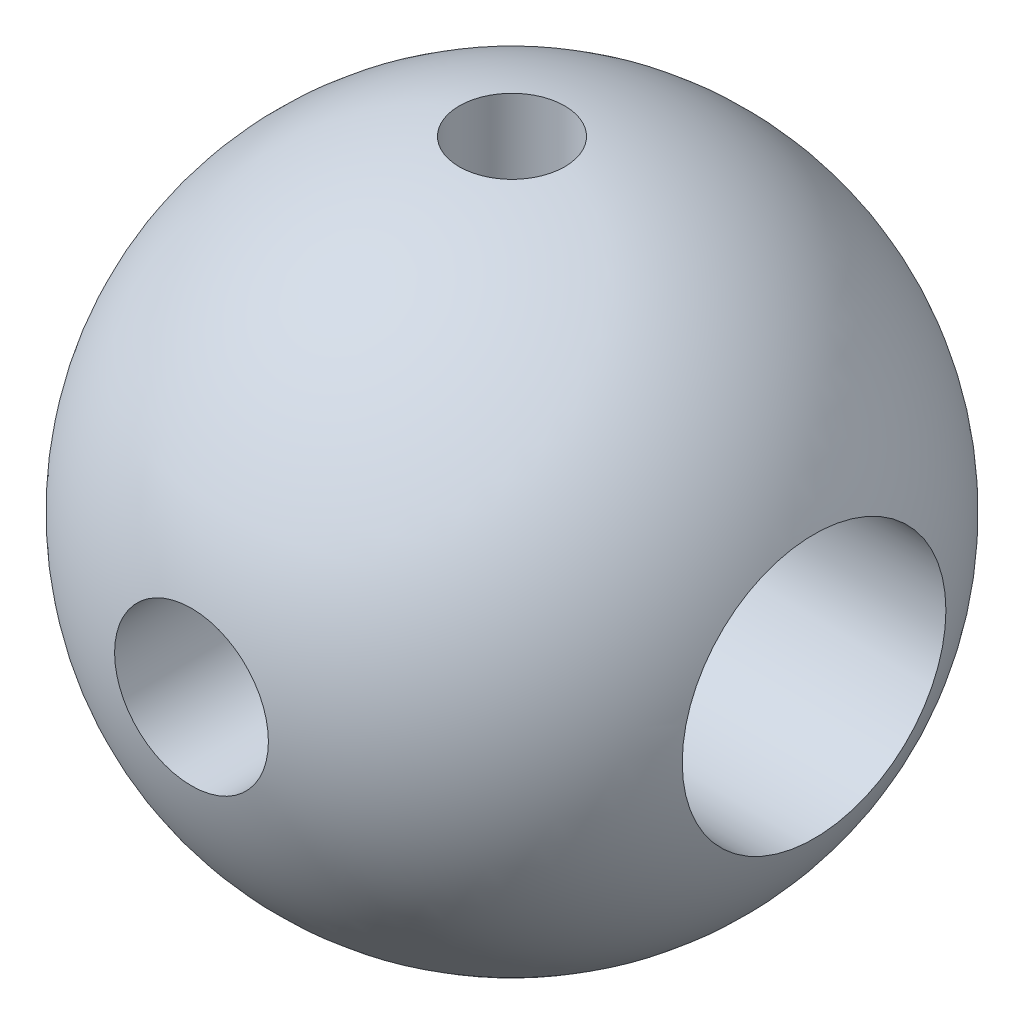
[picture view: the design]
ISO-10303-21;
HEADER;
FILE_DESCRIPTION(('STEP AP214'),'2;1');
FILE_NAME('part.step','',(''),(''),'','','');
FILE_SCHEMA(('AUTOMOTIVE_DESIGN { 1 0 10303 214 1 1 1 1 }'));
ENDSEC;
DATA;
#1=APPLICATION_CONTEXT('core data for automotive mechanical design processes');
#2=APPLICATION_PROTOCOL_DEFINITION('international standard','automotive_design',2000,#1);
#3=PRODUCT_CONTEXT('',#1,'mechanical');
#4=PRODUCT('Part','Part','',(#3));
#5=PRODUCT_RELATED_PRODUCT_CATEGORY('part','',(#4));
#6=PRODUCT_DEFINITION_FORMATION('','',#4);
#7=PRODUCT_DEFINITION_CONTEXT('part definition',#1,'design');
#8=PRODUCT_DEFINITION('design','',#6,#7);
#9=PRODUCT_DEFINITION_SHAPE('','',#8);
#10=(LENGTH_UNIT() NAMED_UNIT(*) SI_UNIT(.MILLI.,.METRE.));
#11=(NAMED_UNIT(*) PLANE_ANGLE_UNIT() SI_UNIT($,.RADIAN.));
#12=(NAMED_UNIT(*) SI_UNIT($,.STERADIAN.) SOLID_ANGLE_UNIT());
#13=UNCERTAINTY_MEASURE_WITH_UNIT(LENGTH_MEASURE(1.E-05),#10,'distance_accuracy_value','');
#14=(GEOMETRIC_REPRESENTATION_CONTEXT(3) GLOBAL_UNCERTAINTY_ASSIGNED_CONTEXT((#13)) GLOBAL_UNIT_ASSIGNED_CONTEXT((#10,
#11,#12)) REPRESENTATION_CONTEXT('',''));
#15=CARTESIAN_POINT('',(0.,0.,0.));
#16=DIRECTION('',(0.,0.,1.));
#17=DIRECTION('',(1.,0.,0.));
#18=AXIS2_PLACEMENT_3D('',#15,#16,#17);
#19=CARTESIAN_POINT('',(0.,0.,-75.));
#20=DIRECTION('',(0.,0.,1.));
#21=DIRECTION('',(1.,0.,0.));
#22=AXIS2_PLACEMENT_3D('',#19,#20,#21);
#23=CYLINDRICAL_SURFACE('',#22,17.5);
#24=CARTESIAN_POINT('',(17.5,0.,-30.));
#25=CARTESIAN_POINT('',(17.4999968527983,0.449810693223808,-29.9999971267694));
#26=CARTESIAN_POINT('',(17.4826284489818,0.899793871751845,-29.9898563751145));
#27=CARTESIAN_POINT('',(17.4133677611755,1.79639765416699,-29.9495342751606));
#28=CARTESIAN_POINT('',(17.361451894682,2.24301575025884,-29.919339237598));
#29=CARTESIAN_POINT('',(17.2236137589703,3.13036631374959,-29.8395660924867));
#30=CARTESIAN_POINT('',(17.1376074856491,3.57108144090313,-29.789940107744));
#31=CARTESIAN_POINT('',(16.9327162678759,4.44222245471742,-29.6725435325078));
#32=CARTESIAN_POINT('',(16.8138366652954,4.8726500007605,-29.6047758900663));
#33=CARTESIAN_POINT('',(16.5452616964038,5.71841043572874,-29.453072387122));
#34=CARTESIAN_POINT('',(16.3957215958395,6.13380743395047,-29.3692181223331));
#35=CARTESIAN_POINT('',(16.0670205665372,6.94940208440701,-29.1869910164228));
#36=CARTESIAN_POINT('',(15.8878585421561,7.34959917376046,-29.0886176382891));
#37=CARTESIAN_POINT('',(15.5016401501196,8.13262843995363,-28.8794824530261));
#38=CARTESIAN_POINT('',(15.2945981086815,8.5154694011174,-28.7687270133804));
#39=CARTESIAN_POINT('',(14.8541334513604,9.26243782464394,-28.5369970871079));
#40=CARTESIAN_POINT('',(14.6207082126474,9.62656342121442,-28.4160215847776));
#41=CARTESIAN_POINT('',(14.1107946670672,10.3609767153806,-28.1569314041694));
#42=CARTESIAN_POINT('',(13.8323977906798,10.7297256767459,-28.0182109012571));
#43=CARTESIAN_POINT('',(13.2486479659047,11.4427112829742,-27.7346638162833));
#44=CARTESIAN_POINT('',(12.9432938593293,11.7869468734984,-27.5898369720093));
#45=CARTESIAN_POINT('',(12.3067916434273,12.4500740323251,-27.2970177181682));
#46=CARTESIAN_POINT('',(11.9756138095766,12.7689355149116,-27.1490218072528));
#47=CARTESIAN_POINT('',(11.2891441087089,13.3796980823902,-26.853283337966));
#48=CARTESIAN_POINT('',(10.9338509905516,13.6715977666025,-26.7055407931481));
#49=CARTESIAN_POINT('',(10.1583817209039,14.259039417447,-26.3970089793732));
#50=CARTESIAN_POINT('',(9.73543487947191,14.5511698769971,-26.2366633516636));
#51=CARTESIAN_POINT('',(8.86283360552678,15.0985250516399,-25.9255412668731));
#52=CARTESIAN_POINT('',(8.41317514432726,15.3537441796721,-25.774766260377));
#53=CARTESIAN_POINT('',(7.48977052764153,15.8247150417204,-25.4883167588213));
#54=CARTESIAN_POINT('',(7.01605587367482,16.0405167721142,-25.3526232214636));
#55=CARTESIAN_POINT('',(6.04663430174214,16.4304876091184,-25.1016518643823));
#56=CARTESIAN_POINT('',(5.55093507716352,16.6046711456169,-24.9863669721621));
#57=CARTESIAN_POINT('',(4.65706076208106,16.8738511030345,-24.8051015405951));
#58=CARTESIAN_POINT('',(4.26263870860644,16.9778465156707,-24.7338784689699));
#59=CARTESIAN_POINT('',(3.46485026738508,17.1584379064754,-24.6089435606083));
#60=CARTESIAN_POINT('',(3.06148523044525,17.2350379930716,-24.5552290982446));
#61=CARTESIAN_POINT('',(2.24867486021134,17.3597911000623,-24.4671923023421));
#62=CARTESIAN_POINT('',(1.8392358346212,17.4079717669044,-24.4328511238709));
#63=CARTESIAN_POINT('',(1.0167506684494,17.475309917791,-24.3847344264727));
#64=CARTESIAN_POINT('',(0.603704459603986,17.4944668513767,-24.3709592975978));
#65=CARTESIAN_POINT('',(-0.223533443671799,17.5034683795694,-24.3644952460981));
#66=CARTESIAN_POINT('',(-0.637725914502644,17.4932661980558,-24.37183997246));
#67=CARTESIAN_POINT('',(-1.46344007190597,17.4436068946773,-24.4074066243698));
#68=CARTESIAN_POINT('',(-1.87496174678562,17.4041496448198,-24.4356286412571));
#69=CARTESIAN_POINT('',(-2.692603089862,17.2965326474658,-24.5119213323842));
#70=CARTESIAN_POINT('',(-3.09871931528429,17.2283554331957,-24.5600040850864));
#71=CARTESIAN_POINT('',(-3.90267086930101,17.0642171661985,-24.674328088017));
#72=CARTESIAN_POINT('',(-4.30050600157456,16.9682554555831,-24.7405697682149));
#73=CARTESIAN_POINT('',(-5.08267223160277,16.7505223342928,-24.8884945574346));
#74=CARTESIAN_POINT('',(-5.46708355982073,16.6289547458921,-24.970055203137));
#75=CARTESIAN_POINT('',(-6.22398496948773,16.3607241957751,-25.1466195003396));
#76=CARTESIAN_POINT('',(-6.59647109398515,16.2140530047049,-25.2416275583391));
#77=CARTESIAN_POINT('',(-7.32806526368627,15.8968063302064,-25.4426176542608));
#78=CARTESIAN_POINT('',(-7.6871723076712,15.7262290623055,-25.5486005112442));
#79=CARTESIAN_POINT('',(-8.39091146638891,15.3622772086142,-25.7690843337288));
#80=CARTESIAN_POINT('',(-8.73554280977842,15.1689014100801,-25.8835857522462));
#81=CARTESIAN_POINT('',(-9.46560202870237,14.7262927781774,-26.1383221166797));
#82=CARTESIAN_POINT('',(-9.84826032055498,14.4731215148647,-26.2796660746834));
#83=CARTESIAN_POINT('',(-10.5913084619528,13.938566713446,-26.5670554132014));
#84=CARTESIAN_POINT('',(-10.9517021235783,13.6571880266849,-26.7130999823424));
#85=CARTESIAN_POINT('',(-11.6494208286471,13.0671312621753,-27.0066427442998));
#86=CARTESIAN_POINT('',(-11.9867237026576,12.7584275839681,-27.1541421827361));
#87=CARTESIAN_POINT('',(-12.6365789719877,12.1151118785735,-27.4472042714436));
#88=CARTESIAN_POINT('',(-12.9491301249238,11.7804985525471,-27.5927668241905));
#89=CARTESIAN_POINT('',(-13.5852520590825,11.0433879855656,-27.8966228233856));
#90=CARTESIAN_POINT('',(-13.905367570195,10.6376217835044,-28.0542511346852));
#91=CARTESIAN_POINT('',(-14.5101413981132,9.79663499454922,-28.358878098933));
#92=CARTESIAN_POINT('',(-14.7947962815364,9.36141156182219,-28.5058757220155));
#93=CARTESIAN_POINT('',(-15.3258939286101,8.46396420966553,-28.7851006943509));
#94=CARTESIAN_POINT('',(-15.5723530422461,8.00175196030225,-28.9173343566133));
#95=CARTESIAN_POINT('',(-16.024383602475,7.0530224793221,-29.1632455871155));
#96=CARTESIAN_POINT('',(-16.2299601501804,6.56650828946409,-29.2769254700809));
#97=CARTESIAN_POINT('',(-16.585129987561,5.60604764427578,-29.4753513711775));
#98=CARTESIAN_POINT('',(-16.7375511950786,5.13344287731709,-29.5615255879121));
#99=CARTESIAN_POINT('',(-17.0022860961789,4.17372530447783,-29.7122175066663));
#100=CARTESIAN_POINT('',(-17.114601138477,3.68661298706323,-29.776735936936));
#101=CARTESIAN_POINT('',(-17.2973035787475,2.70250384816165,-29.8821207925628));
#102=CARTESIAN_POINT('',(-17.3677283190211,2.20551623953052,-29.9230082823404));
#103=CARTESIAN_POINT('',(-17.4656178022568,1.2059347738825,-29.9799298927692));
#104=CARTESIAN_POINT('',(-17.4930878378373,0.703341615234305,-29.9959670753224));
#105=CARTESIAN_POINT('',(-17.5038812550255,-0.238332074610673,-30.0022648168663));
#106=CARTESIAN_POINT('',(-17.4923847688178,-0.677343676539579,-29.9955500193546));
#107=CARTESIAN_POINT('',(-17.4365101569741,-1.55252162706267,-29.962999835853));
#108=CARTESIAN_POINT('',(-17.39213540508,-1.98868826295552,-29.9371664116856));
#109=CARTESIAN_POINT('',(-17.2710852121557,-2.85498146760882,-29.8670045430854));
#110=CARTESIAN_POINT('',(-17.1944102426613,-3.28510812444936,-29.8226763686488));
#111=CARTESIAN_POINT('',(-17.009706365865,-4.13637468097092,-29.7165677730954));
#112=CARTESIAN_POINT('',(-16.9016765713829,-4.55751432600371,-29.654786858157));
#113=CARTESIAN_POINT('',(-16.6574538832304,-5.38154043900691,-29.5162806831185));
#114=CARTESIAN_POINT('',(-16.5217352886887,-5.78461054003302,-29.439808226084));
#115=CARTESIAN_POINT('',(-16.2224830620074,-6.57727299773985,-29.2729147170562));
#116=CARTESIAN_POINT('',(-16.058950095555,-6.96686567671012,-29.1824939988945));
#117=CARTESIAN_POINT('',(-15.7054857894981,-7.73077402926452,-28.989487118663));
#118=CARTESIAN_POINT('',(-15.5155522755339,-8.10508844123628,-28.8868999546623));
#119=CARTESIAN_POINT('',(-15.1107192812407,-8.83691529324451,-28.6714922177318));
#120=CARTESIAN_POINT('',(-14.8958168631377,-9.19442574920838,-28.5586704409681));
#121=CARTESIAN_POINT('',(-14.4187917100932,-9.9276976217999,-28.3126392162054));
#122=CARTESIAN_POINT('',(-14.1540817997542,-10.3014755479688,-28.178530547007));
#123=CARTESIAN_POINT('',(-13.5976432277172,-11.0255438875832,-27.9031798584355));
#124=CARTESIAN_POINT('',(-13.3059129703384,-11.3758329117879,-27.7619374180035));
#125=CARTESIAN_POINT('',(-12.6966614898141,-12.0520590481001,-27.4751323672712));
#126=CARTESIAN_POINT('',(-12.3791126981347,-12.3779693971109,-27.3295652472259));
#127=CARTESIAN_POINT('',(-11.719891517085,-13.0038744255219,-27.0373548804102));
#128=CARTESIAN_POINT('',(-11.3782184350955,-13.3038683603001,-26.8907116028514));
#129=CARTESIAN_POINT('',(-10.629716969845,-13.9110859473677,-26.5821575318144));
#130=CARTESIAN_POINT('',(-10.219984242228,-14.2148796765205,-26.4205194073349));
#131=CARTESIAN_POINT('',(-9.37347588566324,-14.7867809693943,-26.1047476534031));
#132=CARTESIAN_POINT('',(-8.93669617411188,-15.0548831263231,-25.9506151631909));
#133=CARTESIAN_POINT('',(-8.03840403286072,-15.5530565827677,-25.6551405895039));
#134=CARTESIAN_POINT('',(-7.57691649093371,-15.7831652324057,-25.5137860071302));
#135=CARTESIAN_POINT('',(-6.63112032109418,-16.2032645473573,-25.2490774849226));
#136=CARTESIAN_POINT('',(-6.14681879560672,-16.3932675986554,-25.1257179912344));
#137=CARTESIAN_POINT('',(-5.26494928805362,-16.6942555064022,-24.9264319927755));
#138=CARTESIAN_POINT('',(-4.87118142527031,-16.8134449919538,-24.8460125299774));
#139=CARTESIAN_POINT('',(-4.07333959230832,-17.0243377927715,-24.7019890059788));
#140=CARTESIAN_POINT('',(-3.66926705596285,-17.1160449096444,-24.6383826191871));
#141=CARTESIAN_POINT('',(-2.85358320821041,-17.270761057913,-24.5301802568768));
#142=CARTESIAN_POINT('',(-2.44198036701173,-17.3338004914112,-24.4855641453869));
#143=CARTESIAN_POINT('',(-1.61360456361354,-17.430437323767,-24.4168669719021));
#144=CARTESIAN_POINT('',(-1.19683154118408,-17.4640343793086,-24.3927861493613));
#145=CARTESIAN_POINT('',(-0.360120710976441,-17.5013184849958,-24.3660499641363));
#146=CARTESIAN_POINT('',(0.0598226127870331,-17.5049242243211,-24.3634528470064));
#147=CARTESIAN_POINT('',(0.898450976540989,-17.4819549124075,-24.3799394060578));
#148=CARTESIAN_POINT('',(1.3171360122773,-17.4553797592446,-24.3990231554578));
#149=CARTESIAN_POINT('',(2.15025222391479,-17.3724427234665,-24.4581439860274));
#150=CARTESIAN_POINT('',(2.5646810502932,-17.3160652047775,-24.4981920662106));
#151=CARTESIAN_POINT('',(3.38615200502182,-17.1743332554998,-24.5977590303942));
#152=CARTESIAN_POINT('',(3.79319403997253,-17.0889784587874,-24.657278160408));
#153=CARTESIAN_POINT('',(4.58544224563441,-16.8933493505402,-24.7916997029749));
#154=CARTESIAN_POINT('',(4.97093786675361,-16.7838907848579,-24.8660925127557));
#155=CARTESIAN_POINT('',(5.73091273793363,-16.5398304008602,-25.0290936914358));
#156=CARTESIAN_POINT('',(6.10538834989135,-16.4052203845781,-25.11770669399));
#157=CARTESIAN_POINT('',(6.84175460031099,-16.1120287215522,-25.3067765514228));
#158=CARTESIAN_POINT('',(7.20364427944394,-15.9534452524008,-25.407234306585));
#159=CARTESIAN_POINT('',(7.91366058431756,-15.6134217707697,-25.6175920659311));
#160=CARTESIAN_POINT('',(8.26178655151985,-15.4319806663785,-25.7274925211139));
#161=CARTESIAN_POINT('',(8.99622181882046,-15.0174007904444,-25.9719887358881));
#162=CARTESIAN_POINT('',(9.38007737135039,-14.780608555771,-26.1077707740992));
#163=CARTESIAN_POINT('',(10.1268432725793,-14.2793303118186,-26.3852759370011));
#164=CARTESIAN_POINT('',(10.4897570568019,-14.01484886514,-26.5269980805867));
#165=CARTESIAN_POINT('',(11.1938616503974,-13.4591512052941,-26.8132242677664));
#166=CARTESIAN_POINT('',(11.5350346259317,-13.1679135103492,-26.9577304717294));
#167=CARTESIAN_POINT('',(12.1941478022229,-12.5600071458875,-27.2462739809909));
#168=CARTESIAN_POINT('',(12.5120867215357,-12.2433370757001,-27.3903112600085));
#169=CARTESIAN_POINT('',(13.1663568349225,-11.5394613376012,-27.6949046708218));
#170=CARTESIAN_POINT('',(13.4990058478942,-11.1485939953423,-27.8549417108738));
#171=CARTESIAN_POINT('',(14.1302209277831,-10.3368854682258,-28.1662522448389));
#172=CARTESIAN_POINT('',(14.4287831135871,-9.91604087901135,-28.3175247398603));
#173=CARTESIAN_POINT('',(14.9894358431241,-9.046247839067,-28.6072642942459));
#174=CARTESIAN_POINT('',(15.2515119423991,-8.59728835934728,-28.7457262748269));
#175=CARTESIAN_POINT('',(15.7363172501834,-7.67398823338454,-29.0058586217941));
#176=CARTESIAN_POINT('',(15.9590523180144,-7.19965138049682,-29.1275314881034));
#177=CARTESIAN_POINT('',(16.3528613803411,-6.25177433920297,-29.3451946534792));
#178=CARTESIAN_POINT('',(16.5258832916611,-5.77926155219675,-29.4421287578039));
#179=CARTESIAN_POINT('',(16.8314407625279,-4.81738564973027,-29.6147173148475));
#180=CARTESIAN_POINT('',(16.9639692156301,-4.32801959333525,-29.6903680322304));
#181=CARTESIAN_POINT('',(17.1860844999,-3.33838985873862,-29.8178345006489));
#182=CARTESIAN_POINT('',(17.2758169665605,-2.83816928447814,-29.8697310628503));
#183=CARTESIAN_POINT('',(17.4114535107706,-1.83015669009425,-29.948382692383));
#184=CARTESIAN_POINT('',(17.4573967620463,-1.32237185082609,-29.975160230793));
#185=CARTESIAN_POINT('',(17.4873882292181,-0.678004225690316,-29.9926448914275));
#186=CARTESIAN_POINT('',(17.4921161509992,-0.542466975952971,-29.9954016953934));
#187=CARTESIAN_POINT('',(17.4984225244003,-0.271291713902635,-29.9990796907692));
#188=CARTESIAN_POINT('',(17.5000009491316,-0.13565370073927,-30.0000008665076));
#189=CARTESIAN_POINT('',(17.5,0.,-30.));
#190=B_SPLINE_CURVE_WITH_KNOTS('',3,(#24,#25,#26,#27,#28,#29,#30,#31,#32,#33,#34,#35,#36,#37,
#38,#39,#40,#41,#42,#43,#44,#45,#46,#47,#48,#49,#50,#51,#52,#53,#54,#55,#56,#57,#58,#59,#60,#61,
#62,#63,#64,#65,#66,#67,#68,#69,#70,#71,#72,#73,#74,#75,#76,#77,#78,#79,#80,#81,#82,#83,#84,#85,
#86,#87,#88,#89,#90,#91,#92,#93,#94,#95,#96,#97,#98,#99,#100,#101,#102,#103,#104,#105,#106,#107,
#108,#109,#110,#111,#112,#113,#114,#115,#116,#117,#118,#119,#120,#121,#122,#123,#124,#125,#126,
#127,#128,#129,#130,#131,#132,#133,#134,#135,#136,#137,#138,#139,#140,#141,#142,#143,#144,#145,
#146,#147,#148,#149,#150,#151,#152,#153,#154,#155,#156,#157,#158,#159,#160,#161,#162,#163,#164,
#165,#166,#167,#168,#169,#170,#171,#172,#173,#174,#175,#176,#177,#178,#179,#180,#181,#182,#183,
#184,#185,#186,#187,#188,#189),.UNSPECIFIED.,.T.,.F.,(4,2,2,2,2,2,2,2,2,2,2,2,2,2,2,2,2,2,2,2,2,
2,2,2,2,2,2,2,2,2,2,2,2,2,2,2,2,2,2,2,2,2,2,2,2,2,2,2,2,2,2,2,2,2,2,2,2,2,2,2,2,2,2,2,2,2,2,2,2,
2,2,2,2,2,2,2,2,2,2,2,2,2,4),(0.,1.3492851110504,2.69949220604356,4.05304731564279,
5.4063826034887,6.75302671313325,8.09972064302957,9.44572519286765,10.7918636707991,
12.2376383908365,13.6834752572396,15.1310016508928,16.5786032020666,18.1919933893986,
19.8056275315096,21.4172005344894,23.0282139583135,24.2691750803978,25.509950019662,
26.7495159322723,27.9891053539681,29.2306708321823,30.4722417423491,31.7145688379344,
32.9569253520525,34.1897431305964,35.4229658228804,36.6562806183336,37.8896610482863,
39.3285368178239,40.7671655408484,42.2071566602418,43.6472200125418,45.2661955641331,
46.8853277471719,48.503764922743,50.1220000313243,51.6318206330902,53.1415904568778,
54.6500124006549,56.1582484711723,57.474265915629,58.7901483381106,60.106011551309,
61.4219120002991,62.7169231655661,64.0119033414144,65.306990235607,66.6022296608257,
68.0325140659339,69.462882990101,70.8947998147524,72.3267577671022,73.9300541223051,
75.5335930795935,77.1355461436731,78.7370037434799,79.9933457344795,81.249513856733,
82.5043466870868,83.7591941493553,85.0174425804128,86.2756952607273,87.5346087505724,
88.7935381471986,90.015062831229,91.2369863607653,92.4590028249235,93.6810776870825,
95.0927219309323,96.5041339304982,97.9166891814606,99.3293222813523,100.940233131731,
102.551327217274,104.163057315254,105.774547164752,107.309672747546,108.845067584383,
110.375199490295,111.903961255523,112.310874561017,112.717791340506),.UNSPECIFIED.);
#191=CARTESIAN_POINT('',(17.5,0.,-30.));
#192=VERTEX_POINT('',#191);
#193=EDGE_CURVE('E40',#192,#192,#190,.T.);
#194=ORIENTED_EDGE('',*,*,#193,.T.);
#195=EDGE_LOOP('',(#194));
#196=FACE_BOUND('',#195,.T.);
#197=CARTESIAN_POINT('',(0.,0.,-72.9297607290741));
#198=DIRECTION('',(0.,0.,1.));
#199=DIRECTION('',(1.,0.,0.));
#200=AXIS2_PLACEMENT_3D('',#197,#198,#199);
#201=CIRCLE('',#200,17.5);
#202=CARTESIAN_POINT('',(17.5,0.,-72.9297607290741));
#203=VERTEX_POINT('',#202);
#204=EDGE_CURVE('E89',#203,#203,#201,.F.);
#205=ORIENTED_EDGE('',*,*,#204,.T.);
#206=EDGE_LOOP('',(#205));
#207=FACE_BOUND('',#206,.T.);
#208=ADVANCED_FACE('F36',(#196,#207),#23,.F.);
#209=CARTESIAN_POINT('',(0.,-75.,0.));
#210=DIRECTION('',(0.,1.,0.));
#211=DIRECTION('',(0.,0.,1.));
#212=AXIS2_PLACEMENT_3D('',#209,#210,#211);
#213=CYLINDRICAL_SURFACE('',#212,12.);
#214=CARTESIAN_POINT('',(0.,-27.495454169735,12.));
#215=CARTESIAN_POINT('',(0.321531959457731,-27.4954566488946,11.9999975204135));
#216=CARTESIAN_POINT('',(0.643162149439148,-27.5011130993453,11.9870595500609));
#217=CARTESIAN_POINT('',(1.28409771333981,-27.5235570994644,11.9354334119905));
#218=CARTESIAN_POINT('',(1.60340154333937,-27.5403514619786,11.8967294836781));
#219=CARTESIAN_POINT('',(2.23789162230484,-27.5845569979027,11.7938692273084));
#220=CARTESIAN_POINT('',(2.55306682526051,-27.6119922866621,11.7296550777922));
#221=CARTESIAN_POINT('',(3.1762551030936,-27.6765700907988,11.5764572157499));
#222=CARTESIAN_POINT('',(3.48426920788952,-27.7137112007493,11.4874770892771));
#223=CARTESIAN_POINT('',(4.0900150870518,-27.7963760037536,11.2859771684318));
#224=CARTESIAN_POINT('',(4.38778122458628,-27.8418675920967,11.1735473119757));
#225=CARTESIAN_POINT('',(4.97246345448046,-27.9399769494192,10.9259056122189));
#226=CARTESIAN_POINT('',(5.25937918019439,-27.9925949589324,10.7906929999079));
#227=CARTESIAN_POINT('',(5.82062688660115,-28.1034524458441,10.4985875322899));
#228=CARTESIAN_POINT('',(6.09496481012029,-28.1616892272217,10.3417050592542));
#229=CARTESIAN_POINT('',(6.62987508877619,-28.2822790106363,10.0072125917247));
#230=CARTESIAN_POINT('',(6.89044239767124,-28.3446335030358,9.82959507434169));
#231=CARTESIAN_POINT('',(7.40949843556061,-28.4751530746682,9.44505036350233));
#232=CARTESIAN_POINT('',(7.66718313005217,-28.5434518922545,9.23708257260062));
#233=CARTESIAN_POINT('',(8.16436321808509,-28.6809996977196,8.80071497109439));
#234=CARTESIAN_POINT('',(8.40385796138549,-28.7502487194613,8.57231443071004));
#235=CARTESIAN_POINT('',(8.86341257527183,-28.8879212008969,8.09625984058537));
#236=CARTESIAN_POINT('',(9.08346238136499,-28.9563442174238,7.84859594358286));
#237=CARTESIAN_POINT('',(9.50257548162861,-29.0905403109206,7.33557991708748));
#238=CARTESIAN_POINT('',(9.70164600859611,-29.1563142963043,7.07023393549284));
#239=CARTESIAN_POINT('',(10.0850375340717,-29.2860743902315,6.51237726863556));
#240=CARTESIAN_POINT('',(10.2684586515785,-29.3498857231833,6.21920623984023));
#241=CARTESIAN_POINT('',(10.6098125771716,-29.4710477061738,5.61708500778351));
#242=CARTESIAN_POINT('',(10.7677445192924,-29.5283981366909,5.30813426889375));
#243=CARTESIAN_POINT('',(11.056654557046,-29.6349722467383,4.67663438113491));
#244=CARTESIAN_POINT('',(11.187641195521,-29.6841985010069,4.35408958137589));
#245=CARTESIAN_POINT('',(11.4214127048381,-29.7730913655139,3.69766064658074));
#246=CARTESIAN_POINT('',(11.5241993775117,-29.8127585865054,3.36377723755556));
#247=CARTESIAN_POINT('',(11.696190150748,-29.8796737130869,2.70366008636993));
#248=CARTESIAN_POINT('',(11.7667789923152,-29.9074298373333,2.37783837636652));
#249=CARTESIAN_POINT('',(11.8806661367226,-29.9524203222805,1.72073928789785));
#250=CARTESIAN_POINT('',(11.9239652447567,-29.9696549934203,1.3894620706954));
#251=CARTESIAN_POINT('',(11.9827821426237,-29.9931048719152,0.72416735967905));
#252=CARTESIAN_POINT('',(11.9983087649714,-29.9993235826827,0.390150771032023));
#253=CARTESIAN_POINT('',(12.0014293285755,-30.0005716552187,-0.278028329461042));
#254=CARTESIAN_POINT('',(11.9890242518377,-29.9956014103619,-0.612190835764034));
#255=CARTESIAN_POINT('',(11.937909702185,-29.9752095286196,-1.25922099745));
#256=CARTESIAN_POINT('',(11.9007191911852,-29.9603915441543,-1.57222912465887));
#257=CARTESIAN_POINT('',(11.8019665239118,-29.9213027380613,-2.19376209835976));
#258=CARTESIAN_POINT('',(11.7404054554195,-29.8970323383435,-2.50228714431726));
#259=CARTESIAN_POINT('',(11.5934967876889,-29.8396481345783,-3.11278241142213));
#260=CARTESIAN_POINT('',(11.5081483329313,-29.806534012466,-3.41475239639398));
#261=CARTESIAN_POINT('',(11.3144305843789,-29.7322777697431,-4.01019821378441));
#262=CARTESIAN_POINT('',(11.2060606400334,-29.6911354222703,-4.3036738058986));
#263=CARTESIAN_POINT('',(10.9654268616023,-29.6011478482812,-4.88464287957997));
#264=CARTESIAN_POINT('',(10.8328322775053,-29.5521973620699,-5.17198293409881));
#265=CARTESIAN_POINT('',(10.5458462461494,-29.4482085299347,-5.73453367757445));
#266=CARTESIAN_POINT('',(10.3914469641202,-29.3931679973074,-6.00973995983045));
#267=CARTESIAN_POINT('',(10.0619629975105,-29.2783070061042,-6.546454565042));
#268=CARTESIAN_POINT('',(9.88687646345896,-29.2184861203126,-6.8079616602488));
#269=CARTESIAN_POINT('',(9.51714156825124,-29.0954566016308,-7.31592180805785));
#270=CARTESIAN_POINT('',(9.32249217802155,-29.0322477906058,-7.56237406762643));
#271=CARTESIAN_POINT('',(8.90136052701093,-28.899683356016,-8.05465561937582));
#272=CARTESIAN_POINT('',(8.67362711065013,-28.8301967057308,-8.29938050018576));
#273=CARTESIAN_POINT('',(8.19860351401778,-28.6908617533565,-8.76894788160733));
#274=CARTESIAN_POINT('',(7.95131259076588,-28.6210134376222,-8.99378962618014));
#275=CARTESIAN_POINT('',(7.43851904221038,-28.4828123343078,-9.42231968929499));
#276=CARTESIAN_POINT('',(7.17301152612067,-28.4144599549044,-9.62600228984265));
#277=CARTESIAN_POINT('',(6.62529941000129,-28.2811605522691,-10.0108664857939));
#278=CARTESIAN_POINT('',(6.34309288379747,-28.2162139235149,-10.1920454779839));
#279=CARTESIAN_POINT('',(5.75533683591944,-28.0898420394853,-10.5354263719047));
#280=CARTESIAN_POINT('',(5.44935105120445,-28.0285701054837,-10.6969394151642));
#281=CARTESIAN_POINT('',(4.82351875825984,-27.9136487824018,-10.9933382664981));
#282=CARTESIAN_POINT('',(4.50367829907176,-27.8599961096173,-11.128235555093));
#283=CARTESIAN_POINT('',(3.85231465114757,-27.7621453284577,-11.3701506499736));
#284=CARTESIAN_POINT('',(3.52079503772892,-27.717944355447,-11.4771769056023));
#285=CARTESIAN_POINT('',(2.84850092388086,-27.6405954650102,-11.6622282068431));
#286=CARTESIAN_POINT('',(2.50772717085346,-27.6074466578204,-11.7402555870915));
#287=CARTESIAN_POINT('',(1.84075397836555,-27.5551208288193,-11.8625232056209));
#288=CARTESIAN_POINT('',(1.51493615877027,-27.5352139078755,-11.9085364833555));
#289=CARTESIAN_POINT('',(0.860124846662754,-27.5069600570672,-11.9736553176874));
#290=CARTESIAN_POINT('',(0.53113148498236,-27.4986126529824,-11.992761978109));
#291=CARTESIAN_POINT('',(-0.127310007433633,-27.4937783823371,-12.0038404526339));
#292=CARTESIAN_POINT('',(-0.456757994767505,-27.4972883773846,-11.9958194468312));
#293=CARTESIAN_POINT('',(-1.11353938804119,-27.5160357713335,-11.9527539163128));
#294=CARTESIAN_POINT('',(-1.44087284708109,-27.5312728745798,-11.917710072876));
#295=CARTESIAN_POINT('',(-2.07228685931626,-27.5717393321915,-11.823773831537));
#296=CARTESIAN_POINT('',(-2.37662838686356,-27.5963488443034,-11.7663565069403));
#297=CARTESIAN_POINT('',(-2.9791128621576,-27.6547503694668,-11.628429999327));
#298=CARTESIAN_POINT('',(-3.27725609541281,-27.6885419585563,-11.547921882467));
#299=CARTESIAN_POINT('',(-3.86549747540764,-27.7643112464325,-11.364543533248));
#300=CARTESIAN_POINT('',(-4.15559573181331,-27.8062888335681,-11.2616736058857));
#301=CARTESIAN_POINT('',(-4.72619864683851,-27.8972682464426,-11.0343737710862));
#302=CARTESIAN_POINT('',(-5.00669950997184,-27.9462728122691,-10.9099354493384));
#303=CARTESIAN_POINT('',(-5.5675436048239,-28.0520709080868,-10.6350299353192));
#304=CARTESIAN_POINT('',(-5.8474289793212,-28.1090980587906,-10.4837187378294));
#305=CARTESIAN_POINT('',(-6.39370981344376,-28.2277946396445,-10.1597916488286));
#306=CARTESIAN_POINT('',(-6.66009923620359,-28.2894661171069,-9.98716633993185));
#307=CARTESIAN_POINT('',(-7.17793883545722,-28.4158360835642,-9.62172710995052));
#308=CARTESIAN_POINT('',(-7.42938703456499,-28.4805349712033,-9.42891052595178));
#309=CARTESIAN_POINT('',(-7.91605032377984,-28.6113422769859,-9.0242071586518));
#310=CARTESIAN_POINT('',(-8.15126477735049,-28.6774507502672,-8.81231962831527));
#311=CARTESIAN_POINT('',(-8.62106142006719,-28.8143805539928,-8.35420660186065));
#312=CARTESIAN_POINT('',(-8.85430323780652,-28.8851878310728,-8.10659993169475));
#313=CARTESIAN_POINT('',(-9.29912344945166,-29.0246291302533,-7.59222484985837));
#314=CARTESIAN_POINT('',(-9.51070925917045,-29.0932638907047,-7.32546305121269));
#315=CARTESIAN_POINT('',(-9.91093038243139,-29.2265448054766,-6.77417927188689));
#316=CARTESIAN_POINT('',(-10.0995594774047,-29.2911898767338,-6.48965251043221));
#317=CARTESIAN_POINT('',(-10.4523701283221,-29.4147025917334,-5.90462800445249));
#318=CARTESIAN_POINT('',(-10.6165522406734,-29.4735703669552,-5.60413062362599));
#319=CARTESIAN_POINT('',(-10.9190644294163,-29.5838828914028,-4.98913207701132));
#320=CARTESIAN_POINT('',(-11.0573986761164,-29.6353288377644,-4.67463318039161));
#321=CARTESIAN_POINT('',(-11.3069491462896,-29.7293412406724,-4.03375050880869));
#322=CARTESIAN_POINT('',(-11.4181651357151,-29.771907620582,-3.70736663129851));
#323=CARTESIAN_POINT('',(-11.6122831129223,-29.8468943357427,-3.04529606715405));
#324=CARTESIAN_POINT('',(-11.6951977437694,-29.8793192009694,-2.70961360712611));
#325=CARTESIAN_POINT('',(-11.8318487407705,-29.9330701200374,-2.03149214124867));
#326=CARTESIAN_POINT('',(-11.8855870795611,-29.9543969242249,-1.68905359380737));
#327=CARTESIAN_POINT('',(-11.9607208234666,-29.9842916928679,-1.02279244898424));
#328=CARTESIAN_POINT('',(-11.9839987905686,-29.9936017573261,-0.699214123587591));
#329=CARTESIAN_POINT('',(-12.0042694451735,-30.0017065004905,-0.0511105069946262));
#330=CARTESIAN_POINT('',(-12.0012633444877,-30.0005016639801,0.273414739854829));
#331=CARTESIAN_POINT('',(-11.9690019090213,-29.9876106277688,0.920898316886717));
#332=CARTESIAN_POINT('',(-11.939750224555,-29.9759258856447,1.24385685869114));
#333=CARTESIAN_POINT('',(-11.8553139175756,-29.9423941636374,1.88582722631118));
#334=CARTESIAN_POINT('',(-11.8001293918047,-29.9205472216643,2.20483906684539));
#335=CARTESIAN_POINT('',(-11.6664880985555,-29.8680982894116,2.82685665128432));
#336=CARTESIAN_POINT('',(-11.5888004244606,-29.8377866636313,3.13005276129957));
#337=CARTESIAN_POINT('',(-11.4103102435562,-29.7689167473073,3.72858474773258));
#338=CARTESIAN_POINT('',(-11.3095083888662,-29.7303586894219,4.02392084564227));
#339=CARTESIAN_POINT('',(-11.0856479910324,-29.645924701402,4.60492442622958));
#340=CARTESIAN_POINT('',(-10.9625905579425,-29.6000491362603,4.89059239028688));
#341=CARTESIAN_POINT('',(-10.6951215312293,-29.5020362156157,5.45075699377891));
#342=CARTESIAN_POINT('',(-10.5507016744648,-29.4498964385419,5.72524925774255));
#343=CARTESIAN_POINT('',(-10.2347884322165,-29.3381683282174,6.27323333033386));
#344=CARTESIAN_POINT('',(-10.0623866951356,-29.2783538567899,6.54615543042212));
#345=CARTESIAN_POINT('',(-9.69658092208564,-29.1546573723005,7.07673702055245));
#346=CARTESIAN_POINT('',(-9.50316748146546,-29.090773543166,7.33438959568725));
#347=CARTESIAN_POINT('',(-9.09658226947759,-28.9605028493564,7.83298688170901));
#348=CARTESIAN_POINT('',(-8.88340759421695,-28.894115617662,8.07392912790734));
#349=CARTESIAN_POINT('',(-8.43854658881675,-28.760460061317,8.53781079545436));
#350=CARTESIAN_POINT('',(-8.20685969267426,-28.6931917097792,8.76074966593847));
#351=CARTESIAN_POINT('',(-7.71126124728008,-28.5552700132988,9.20070417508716));
#352=CARTESIAN_POINT('',(-7.44624172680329,-28.4846663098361,9.41648929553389));
#353=CARTESIAN_POINT('',(-6.89836742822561,-28.3463798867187,9.82492926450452));
#354=CARTESIAN_POINT('',(-6.61551872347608,-28.2786961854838,10.0175919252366));
#355=CARTESIAN_POINT('',(-6.03344233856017,-28.1482142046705,10.3785788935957));
#356=CARTESIAN_POINT('',(-5.73420788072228,-28.0854179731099,10.5468930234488));
#357=CARTESIAN_POINT('',(-5.12133640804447,-27.966725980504,10.8577129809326));
#358=CARTESIAN_POINT('',(-4.80770140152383,-27.9108292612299,11.000222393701));
#359=CARTESIAN_POINT('',(-4.19681478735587,-27.8124200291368,11.2465671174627));
#360=CARTESIAN_POINT('',(-3.90061941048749,-27.7691565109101,11.3527256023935));
#361=CARTESIAN_POINT('',(-3.2997893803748,-27.6911526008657,11.5416866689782));
#362=CARTESIAN_POINT('',(-2.9951557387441,-27.6564111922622,11.6244920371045));
#363=CARTESIAN_POINT('',(-2.38015283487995,-27.5965881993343,11.7658063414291));
#364=CARTESIAN_POINT('',(-2.0697990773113,-27.5714836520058,11.8243730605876));
#365=CARTESIAN_POINT('',(-1.44491103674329,-27.5316304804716,11.9168740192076));
#366=CARTESIAN_POINT('',(-1.13037928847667,-27.5168758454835,11.9508225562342));
#367=CARTESIAN_POINT('',(-0.679349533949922,-27.5035106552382,11.9815263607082));
#368=CARTESIAN_POINT('',(-0.543600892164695,-27.5004918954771,11.9884515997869));
#369=CARTESIAN_POINT('',(-0.271907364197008,-27.4964630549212,11.9976891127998));
#370=CARTESIAN_POINT('',(-0.135962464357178,-27.4954531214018,12.0000010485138));
#371=CARTESIAN_POINT('',(0.,-27.495454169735,12.));
#372=B_SPLINE_CURVE_WITH_KNOTS('',3,(#214,#215,#216,#217,#218,#219,#220,#221,#222,#223,#224,
#225,#226,#227,#228,#229,#230,#231,#232,#233,#234,#235,#236,#237,#238,#239,#240,#241,#242,#243,
#244,#245,#246,#247,#248,#249,#250,#251,#252,#253,#254,#255,#256,#257,#258,#259,#260,#261,#262,
#263,#264,#265,#266,#267,#268,#269,#270,#271,#272,#273,#274,#275,#276,#277,#278,#279,#280,#281,
#282,#283,#284,#285,#286,#287,#288,#289,#290,#291,#292,#293,#294,#295,#296,#297,#298,#299,#300,
#301,#302,#303,#304,#305,#306,#307,#308,#309,#310,#311,#312,#313,#314,#315,#316,#317,#318,#319,
#320,#321,#322,#323,#324,#325,#326,#327,#328,#329,#330,#331,#332,#333,#334,#335,#336,#337,#338,
#339,#340,#341,#342,#343,#344,#345,#346,#347,#348,#349,#350,#351,#352,#353,#354,#355,#356,#357,
#358,#359,#360,#361,#362,#363,#364,#365,#366,#367,#368,#369,#370,#371),.UNSPECIFIED.,.T.,.F.,(4,
2,2,2,2,2,2,2,2,2,2,2,2,2,2,2,2,2,2,2,2,2,2,2,2,2,2,2,2,2,2,2,2,2,2,2,2,2,2,2,2,2,2,2,2,2,2,2,2,
2,2,2,2,2,2,2,2,2,2,2,2,2,2,2,2,2,2,2,2,2,2,2,2,2,2,2,2,2,4),(0.,0.964458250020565,
1.92950698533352,2.89675569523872,3.86386442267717,4.82732999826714,5.7908281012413,
6.753866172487,7.71725473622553,8.73045394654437,9.74368935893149,10.7574461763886,
11.7708523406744,12.8245096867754,13.8782028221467,14.9315613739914,15.9848526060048,
16.9871588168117,17.9894354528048,18.991393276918,19.9933158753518,20.938877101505,
21.8843961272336,22.8299491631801,23.7755289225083,24.7351424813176,25.6951017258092,
26.6551468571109,27.6152425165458,28.6384069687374,29.6616103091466,30.68508944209,
31.7086868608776,32.761486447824,33.8138309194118,34.8658559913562,35.9177963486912,
36.9054658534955,37.8930948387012,38.8804624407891,39.867805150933,40.7988037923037,
41.7297594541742,42.6607024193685,43.5920093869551,44.5606818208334,45.5297837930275,
46.4990137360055,47.4682816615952,48.5094270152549,49.550214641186,50.5912835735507,
51.6323288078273,52.6732059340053,53.7140920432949,54.7545125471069,55.7948626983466,
56.767289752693,57.7396719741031,58.7119189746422,59.6841623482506,60.6264621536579,
61.5687353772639,62.5109616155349,63.4535532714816,64.4374037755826,65.4216964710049,
66.4061340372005,67.3906017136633,68.4362909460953,69.4816258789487,70.5273965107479,
71.5730217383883,72.5247944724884,73.4764535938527,74.4258307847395,75.3746561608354,
75.7824554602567,76.1902846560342),.UNSPECIFIED.);
#373=CARTESIAN_POINT('',(0.,-27.495454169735,12.));
#374=VERTEX_POINT('',#373);
#375=EDGE_CURVE('E84',#374,#374,#372,.T.);
#376=ORIENTED_EDGE('',*,*,#375,.T.);
#377=EDGE_LOOP('',(#376));
#378=FACE_BOUND('',#377,.T.);
#379=CARTESIAN_POINT('',(0.,-74.0337760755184,0.));
#380=DIRECTION('',(0.,1.,0.));
#381=DIRECTION('',(0.,0.,1.));
#382=AXIS2_PLACEMENT_3D('',#379,#380,#381);
#383=CIRCLE('',#382,12.);
#384=CARTESIAN_POINT('',(0.,-74.0337760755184,12.));
#385=VERTEX_POINT('',#384);
#386=EDGE_CURVE('E48',#385,#385,#383,.F.);
#387=ORIENTED_EDGE('',*,*,#386,.T.);
#388=EDGE_LOOP('',(#387));
#389=FACE_BOUND('',#388,.T.);
#390=ADVANCED_FACE('F82',(#378,#389),#213,.F.);
#391=CARTESIAN_POINT('',(0.,0.,0.));
#392=DIRECTION('',(0.,1.,0.));
#393=DIRECTION('',(1.,0.,0.));
#394=AXIS2_PLACEMENT_3D('',#391,#392,#393);
#395=SPHERICAL_SURFACE('',#394,75.);
#396=CARTESIAN_POINT('',(68.7386354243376,0.,0.));
#397=DIRECTION('',(-1.,0.,0.));
#398=DIRECTION('',(0.,0.,1.));
#399=AXIS2_PLACEMENT_3D('',#396,#397,#398);
#400=CIRCLE('',#399,30.);
#401=CARTESIAN_POINT('',(68.7386354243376,0.,30.));
#402=VERTEX_POINT('',#401);
#403=EDGE_CURVE('E90',#402,#402,#400,.F.);
#404=ORIENTED_EDGE('',*,*,#403,.F.);
#405=EDGE_LOOP('',(#404));
#406=FACE_BOUND('',#405,.T.);
#407=CARTESIAN_POINT('',(-68.7386354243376,0.,0.));
#408=DIRECTION('',(1.,0.,0.));
#409=DIRECTION('',(0.,0.,-1.));
#410=AXIS2_PLACEMENT_3D('',#407,#408,#409);
#411=CIRCLE('',#410,30.);
#412=CARTESIAN_POINT('',(-68.7386354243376,0.,-30.));
#413=VERTEX_POINT('',#412);
#414=EDGE_CURVE('E76',#413,#413,#411,.F.);
#415=ORIENTED_EDGE('',*,*,#414,.F.);
#416=EDGE_LOOP('',(#415));
#417=FACE_BOUND('',#416,.T.);
#418=CARTESIAN_POINT('',(0.,0.,72.9297607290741));
#419=DIRECTION('',(0.,0.,-1.));
#420=DIRECTION('',(-1.,0.,0.));
#421=AXIS2_PLACEMENT_3D('',#418,#419,#420);
#422=CIRCLE('',#421,17.5);
#423=CARTESIAN_POINT('',(-17.5,0.,72.9297607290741));
#424=VERTEX_POINT('',#423);
#425=EDGE_CURVE('E53',#424,#424,#422,.F.);
#426=ORIENTED_EDGE('',*,*,#425,.F.);
#427=EDGE_LOOP('',(#426));
#428=FACE_BOUND('',#427,.T.);
#429=ORIENTED_EDGE('',*,*,#204,.F.);
#430=EDGE_LOOP('',(#429));
#431=FACE_BOUND('',#430,.T.);
#432=CARTESIAN_POINT('',(0.,74.0337760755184,0.));
#433=DIRECTION('',(0.,-1.,0.));
#434=DIRECTION('',(0.,0.,-1.));
#435=AXIS2_PLACEMENT_3D('',#432,#433,#434);
#436=CIRCLE('',#435,12.);
#437=CARTESIAN_POINT('',(0.,74.0337760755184,-12.));
#438=VERTEX_POINT('',#437);
#439=EDGE_CURVE('E10',#438,#438,#436,.F.);
#440=ORIENTED_EDGE('',*,*,#439,.F.);
#441=EDGE_LOOP('',(#440));
#442=FACE_BOUND('',#441,.T.);
#443=ORIENTED_EDGE('',*,*,#386,.F.);
#444=EDGE_LOOP('',(#443));
#445=FACE_BOUND('',#444,.T.);
#446=ADVANCED_FACE('F38',(#406,#417,#428,#431,#442,#445),#395,.T.);
#447=CARTESIAN_POINT('',(0.,27.495454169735,12.));
#448=CARTESIAN_POINT('',(-0.321531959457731,27.4954566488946,11.9999975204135));
#449=CARTESIAN_POINT('',(-0.643162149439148,27.5011130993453,11.9870595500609));
#450=CARTESIAN_POINT('',(-1.28409771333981,27.5235570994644,11.9354334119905));
#451=CARTESIAN_POINT('',(-1.60340154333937,27.5403514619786,11.8967294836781));
#452=CARTESIAN_POINT('',(-2.23789162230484,27.5845569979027,11.7938692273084));
#453=CARTESIAN_POINT('',(-2.55306682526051,27.6119922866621,11.7296550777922));
#454=CARTESIAN_POINT('',(-3.1762551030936,27.6765700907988,11.5764572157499));
#455=CARTESIAN_POINT('',(-3.48426920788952,27.7137112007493,11.4874770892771));
#456=CARTESIAN_POINT('',(-4.0900150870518,27.7963760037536,11.2859771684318));
#457=CARTESIAN_POINT('',(-4.38778122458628,27.8418675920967,11.1735473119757));
#458=CARTESIAN_POINT('',(-4.97246345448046,27.9399769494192,10.9259056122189));
#459=CARTESIAN_POINT('',(-5.25937918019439,27.9925949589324,10.7906929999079));
#460=CARTESIAN_POINT('',(-5.82062688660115,28.1034524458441,10.4985875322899));
#461=CARTESIAN_POINT('',(-6.09496481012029,28.1616892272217,10.3417050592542));
#462=CARTESIAN_POINT('',(-6.62987508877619,28.2822790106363,10.0072125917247));
#463=CARTESIAN_POINT('',(-6.89044239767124,28.3446335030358,9.82959507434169));
#464=CARTESIAN_POINT('',(-7.40949843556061,28.4751530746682,9.44505036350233));
#465=CARTESIAN_POINT('',(-7.66718313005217,28.5434518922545,9.23708257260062));
#466=CARTESIAN_POINT('',(-8.16436321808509,28.6809996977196,8.80071497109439));
#467=CARTESIAN_POINT('',(-8.40385796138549,28.7502487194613,8.57231443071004));
#468=CARTESIAN_POINT('',(-8.86341257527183,28.8879212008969,8.09625984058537));
#469=CARTESIAN_POINT('',(-9.08346238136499,28.9563442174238,7.84859594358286));
#470=CARTESIAN_POINT('',(-9.50257548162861,29.0905403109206,7.33557991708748));
#471=CARTESIAN_POINT('',(-9.70164600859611,29.1563142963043,7.07023393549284));
#472=CARTESIAN_POINT('',(-10.0850375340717,29.2860743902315,6.51237726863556));
#473=CARTESIAN_POINT('',(-10.2684586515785,29.3498857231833,6.21920623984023));
#474=CARTESIAN_POINT('',(-10.6098125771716,29.4710477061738,5.61708500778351));
#475=CARTESIAN_POINT('',(-10.7677445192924,29.5283981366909,5.30813426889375));
#476=CARTESIAN_POINT('',(-11.056654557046,29.6349722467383,4.67663438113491));
#477=CARTESIAN_POINT('',(-11.187641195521,29.6841985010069,4.35408958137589));
#478=CARTESIAN_POINT('',(-11.4214127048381,29.7730913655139,3.69766064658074));
#479=CARTESIAN_POINT('',(-11.5241993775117,29.8127585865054,3.36377723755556));
#480=CARTESIAN_POINT('',(-11.696190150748,29.8796737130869,2.70366008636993));
#481=CARTESIAN_POINT('',(-11.7667789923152,29.9074298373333,2.37783837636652));
#482=CARTESIAN_POINT('',(-11.8806661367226,29.9524203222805,1.72073928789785));
#483=CARTESIAN_POINT('',(-11.9239652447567,29.9696549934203,1.3894620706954));
#484=CARTESIAN_POINT('',(-11.9827821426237,29.9931048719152,0.72416735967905));
#485=CARTESIAN_POINT('',(-11.9983087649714,29.9993235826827,0.390150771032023));
#486=CARTESIAN_POINT('',(-12.0014293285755,30.0005716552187,-0.278028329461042));
#487=CARTESIAN_POINT('',(-11.9890242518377,29.9956014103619,-0.612190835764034));
#488=CARTESIAN_POINT('',(-11.937909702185,29.9752095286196,-1.25922099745));
#489=CARTESIAN_POINT('',(-11.9007191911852,29.9603915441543,-1.57222912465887));
#490=CARTESIAN_POINT('',(-11.8019665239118,29.9213027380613,-2.19376209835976));
#491=CARTESIAN_POINT('',(-11.7404054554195,29.8970323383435,-2.50228714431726));
#492=CARTESIAN_POINT('',(-11.5934967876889,29.8396481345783,-3.11278241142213));
#493=CARTESIAN_POINT('',(-11.5081483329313,29.806534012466,-3.41475239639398));
#494=CARTESIAN_POINT('',(-11.3144305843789,29.7322777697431,-4.01019821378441));
#495=CARTESIAN_POINT('',(-11.2060606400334,29.6911354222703,-4.3036738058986));
#496=CARTESIAN_POINT('',(-10.9654268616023,29.6011478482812,-4.88464287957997));
#497=CARTESIAN_POINT('',(-10.8328322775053,29.5521973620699,-5.17198293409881));
#498=CARTESIAN_POINT('',(-10.5458462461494,29.4482085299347,-5.73453367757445));
#499=CARTESIAN_POINT('',(-10.3914469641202,29.3931679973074,-6.00973995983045));
#500=CARTESIAN_POINT('',(-10.0619629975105,29.2783070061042,-6.546454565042));
#501=CARTESIAN_POINT('',(-9.88687646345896,29.2184861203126,-6.8079616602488));
#502=CARTESIAN_POINT('',(-9.51714156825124,29.0954566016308,-7.31592180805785));
#503=CARTESIAN_POINT('',(-9.32249217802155,29.0322477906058,-7.56237406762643));
#504=CARTESIAN_POINT('',(-8.90136052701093,28.899683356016,-8.05465561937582));
#505=CARTESIAN_POINT('',(-8.67362711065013,28.8301967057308,-8.29938050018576));
#506=CARTESIAN_POINT('',(-8.19860351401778,28.6908617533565,-8.76894788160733));
#507=CARTESIAN_POINT('',(-7.95131259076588,28.6210134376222,-8.99378962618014));
#508=CARTESIAN_POINT('',(-7.43851904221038,28.4828123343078,-9.42231968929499));
#509=CARTESIAN_POINT('',(-7.17301152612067,28.4144599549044,-9.62600228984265));
#510=CARTESIAN_POINT('',(-6.62529941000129,28.2811605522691,-10.0108664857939));
#511=CARTESIAN_POINT('',(-6.34309288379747,28.2162139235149,-10.1920454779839));
#512=CARTESIAN_POINT('',(-5.75533683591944,28.0898420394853,-10.5354263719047));
#513=CARTESIAN_POINT('',(-5.44935105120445,28.0285701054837,-10.6969394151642));
#514=CARTESIAN_POINT('',(-4.82351875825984,27.9136487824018,-10.9933382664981));
#515=CARTESIAN_POINT('',(-4.50367829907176,27.8599961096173,-11.128235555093));
#516=CARTESIAN_POINT('',(-3.85231465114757,27.7621453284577,-11.3701506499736));
#517=CARTESIAN_POINT('',(-3.52079503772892,27.717944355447,-11.4771769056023));
#518=CARTESIAN_POINT('',(-2.84850092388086,27.6405954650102,-11.6622282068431));
#519=CARTESIAN_POINT('',(-2.50772717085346,27.6074466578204,-11.7402555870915));
#520=CARTESIAN_POINT('',(-1.84075397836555,27.5551208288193,-11.8625232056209));
#521=CARTESIAN_POINT('',(-1.51493615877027,27.5352139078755,-11.9085364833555));
#522=CARTESIAN_POINT('',(-0.860124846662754,27.5069600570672,-11.9736553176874));
#523=CARTESIAN_POINT('',(-0.53113148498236,27.4986126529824,-11.992761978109));
#524=CARTESIAN_POINT('',(0.127310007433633,27.4937783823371,-12.0038404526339));
#525=CARTESIAN_POINT('',(0.456757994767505,27.4972883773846,-11.9958194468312));
#526=CARTESIAN_POINT('',(1.11353938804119,27.5160357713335,-11.9527539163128));
#527=CARTESIAN_POINT('',(1.44087284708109,27.5312728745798,-11.917710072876));
#528=CARTESIAN_POINT('',(2.07228685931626,27.5717393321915,-11.823773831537));
#529=CARTESIAN_POINT('',(2.37662838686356,27.5963488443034,-11.7663565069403));
#530=CARTESIAN_POINT('',(2.9791128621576,27.6547503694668,-11.628429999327));
#531=CARTESIAN_POINT('',(3.27725609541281,27.6885419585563,-11.547921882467));
#532=CARTESIAN_POINT('',(3.86549747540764,27.7643112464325,-11.364543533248));
#533=CARTESIAN_POINT('',(4.15559573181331,27.8062888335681,-11.2616736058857));
#534=CARTESIAN_POINT('',(4.72619864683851,27.8972682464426,-11.0343737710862));
#535=CARTESIAN_POINT('',(5.00669950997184,27.9462728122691,-10.9099354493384));
#536=CARTESIAN_POINT('',(5.5675436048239,28.0520709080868,-10.6350299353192));
#537=CARTESIAN_POINT('',(5.8474289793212,28.1090980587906,-10.4837187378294));
#538=CARTESIAN_POINT('',(6.39370981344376,28.2277946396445,-10.1597916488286));
#539=CARTESIAN_POINT('',(6.66009923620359,28.2894661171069,-9.98716633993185));
#540=CARTESIAN_POINT('',(7.17793883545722,28.4158360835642,-9.62172710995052));
#541=CARTESIAN_POINT('',(7.42938703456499,28.4805349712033,-9.42891052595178));
#542=CARTESIAN_POINT('',(7.91605032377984,28.6113422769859,-9.0242071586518));
#543=CARTESIAN_POINT('',(8.15126477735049,28.6774507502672,-8.81231962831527));
#544=CARTESIAN_POINT('',(8.62106142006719,28.8143805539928,-8.35420660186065));
#545=CARTESIAN_POINT('',(8.85430323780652,28.8851878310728,-8.10659993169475));
#546=CARTESIAN_POINT('',(9.29912344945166,29.0246291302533,-7.59222484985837));
#547=CARTESIAN_POINT('',(9.51070925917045,29.0932638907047,-7.32546305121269));
#548=CARTESIAN_POINT('',(9.91093038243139,29.2265448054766,-6.77417927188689));
#549=CARTESIAN_POINT('',(10.0995594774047,29.2911898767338,-6.48965251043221));
#550=CARTESIAN_POINT('',(10.4523701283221,29.4147025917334,-5.90462800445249));
#551=CARTESIAN_POINT('',(10.6165522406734,29.4735703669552,-5.60413062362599));
#552=CARTESIAN_POINT('',(10.9190644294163,29.5838828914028,-4.98913207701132));
#553=CARTESIAN_POINT('',(11.0573986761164,29.6353288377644,-4.67463318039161));
#554=CARTESIAN_POINT('',(11.3069491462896,29.7293412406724,-4.03375050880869));
#555=CARTESIAN_POINT('',(11.4181651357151,29.771907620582,-3.70736663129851));
#556=CARTESIAN_POINT('',(11.6122831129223,29.8468943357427,-3.04529606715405));
#557=CARTESIAN_POINT('',(11.6951977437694,29.8793192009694,-2.70961360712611));
#558=CARTESIAN_POINT('',(11.8318487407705,29.9330701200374,-2.03149214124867));
#559=CARTESIAN_POINT('',(11.8855870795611,29.9543969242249,-1.68905359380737));
#560=CARTESIAN_POINT('',(11.9607208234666,29.9842916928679,-1.02279244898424));
#561=CARTESIAN_POINT('',(11.9839987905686,29.9936017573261,-0.699214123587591));
#562=CARTESIAN_POINT('',(12.0042694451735,30.0017065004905,-0.0511105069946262));
#563=CARTESIAN_POINT('',(12.0012633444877,30.0005016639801,0.273414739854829));
#564=CARTESIAN_POINT('',(11.9690019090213,29.9876106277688,0.920898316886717));
#565=CARTESIAN_POINT('',(11.939750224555,29.9759258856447,1.24385685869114));
#566=CARTESIAN_POINT('',(11.8553139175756,29.9423941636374,1.88582722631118));
#567=CARTESIAN_POINT('',(11.8001293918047,29.9205472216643,2.20483906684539));
#568=CARTESIAN_POINT('',(11.6664880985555,29.8680982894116,2.82685665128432));
#569=CARTESIAN_POINT('',(11.5888004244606,29.8377866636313,3.13005276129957));
#570=CARTESIAN_POINT('',(11.4103102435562,29.7689167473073,3.72858474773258));
#571=CARTESIAN_POINT('',(11.3095083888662,29.7303586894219,4.02392084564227));
#572=CARTESIAN_POINT('',(11.0856479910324,29.645924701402,4.60492442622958));
#573=CARTESIAN_POINT('',(10.9625905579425,29.6000491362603,4.89059239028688));
#574=CARTESIAN_POINT('',(10.6951215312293,29.5020362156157,5.45075699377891));
#575=CARTESIAN_POINT('',(10.5507016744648,29.4498964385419,5.72524925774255));
#576=CARTESIAN_POINT('',(10.2347884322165,29.3381683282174,6.27323333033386));
#577=CARTESIAN_POINT('',(10.0623866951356,29.2783538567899,6.54615543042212));
#578=CARTESIAN_POINT('',(9.69658092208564,29.1546573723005,7.07673702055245));
#579=CARTESIAN_POINT('',(9.50316748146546,29.090773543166,7.33438959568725));
#580=CARTESIAN_POINT('',(9.09658226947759,28.9605028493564,7.83298688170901));
#581=CARTESIAN_POINT('',(8.88340759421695,28.894115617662,8.07392912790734));
#582=CARTESIAN_POINT('',(8.43854658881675,28.760460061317,8.53781079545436));
#583=CARTESIAN_POINT('',(8.20685969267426,28.6931917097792,8.76074966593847));
#584=CARTESIAN_POINT('',(7.71126124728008,28.5552700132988,9.20070417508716));
#585=CARTESIAN_POINT('',(7.44624172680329,28.4846663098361,9.41648929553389));
#586=CARTESIAN_POINT('',(6.89836742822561,28.3463798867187,9.82492926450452));
#587=CARTESIAN_POINT('',(6.61551872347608,28.2786961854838,10.0175919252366));
#588=CARTESIAN_POINT('',(6.03344233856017,28.1482142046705,10.3785788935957));
#589=CARTESIAN_POINT('',(5.73420788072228,28.0854179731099,10.5468930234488));
#590=CARTESIAN_POINT('',(5.12133640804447,27.966725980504,10.8577129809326));
#591=CARTESIAN_POINT('',(4.80770140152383,27.9108292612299,11.000222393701));
#592=CARTESIAN_POINT('',(4.19681478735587,27.8124200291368,11.2465671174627));
#593=CARTESIAN_POINT('',(3.90061941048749,27.7691565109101,11.3527256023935));
#594=CARTESIAN_POINT('',(3.2997893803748,27.6911526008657,11.5416866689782));
#595=CARTESIAN_POINT('',(2.9951557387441,27.6564111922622,11.6244920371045));
#596=CARTESIAN_POINT('',(2.38015283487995,27.5965881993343,11.7658063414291));
#597=CARTESIAN_POINT('',(2.0697990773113,27.5714836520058,11.8243730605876));
#598=CARTESIAN_POINT('',(1.44491103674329,27.5316304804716,11.9168740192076));
#599=CARTESIAN_POINT('',(1.13037928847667,27.5168758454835,11.9508225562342));
#600=CARTESIAN_POINT('',(0.679349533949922,27.5035106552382,11.9815263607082));
#601=CARTESIAN_POINT('',(0.543600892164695,27.5004918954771,11.9884515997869));
#602=CARTESIAN_POINT('',(0.271907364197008,27.4964630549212,11.9976891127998));
#603=CARTESIAN_POINT('',(0.135962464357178,27.4954531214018,12.0000010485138));
#604=CARTESIAN_POINT('',(0.,27.495454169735,12.));
#605=B_SPLINE_CURVE_WITH_KNOTS('',3,(#447,#448,#449,#450,#451,#452,#453,#454,#455,#456,#457,
#458,#459,#460,#461,#462,#463,#464,#465,#466,#467,#468,#469,#470,#471,#472,#473,#474,#475,#476,
#477,#478,#479,#480,#481,#482,#483,#484,#485,#486,#487,#488,#489,#490,#491,#492,#493,#494,#495,
#496,#497,#498,#499,#500,#501,#502,#503,#504,#505,#506,#507,#508,#509,#510,#511,#512,#513,#514,
#515,#516,#517,#518,#519,#520,#521,#522,#523,#524,#525,#526,#527,#528,#529,#530,#531,#532,#533,
#534,#535,#536,#537,#538,#539,#540,#541,#542,#543,#544,#545,#546,#547,#548,#549,#550,#551,#552,
#553,#554,#555,#556,#557,#558,#559,#560,#561,#562,#563,#564,#565,#566,#567,#568,#569,#570,#571,
#572,#573,#574,#575,#576,#577,#578,#579,#580,#581,#582,#583,#584,#585,#586,#587,#588,#589,#590,
#591,#592,#593,#594,#595,#596,#597,#598,#599,#600,#601,#602,#603,#604),.UNSPECIFIED.,.T.,.F.,(4,
2,2,2,2,2,2,2,2,2,2,2,2,2,2,2,2,2,2,2,2,2,2,2,2,2,2,2,2,2,2,2,2,2,2,2,2,2,2,2,2,2,2,2,2,2,2,2,2,
2,2,2,2,2,2,2,2,2,2,2,2,2,2,2,2,2,2,2,2,2,2,2,2,2,2,2,2,2,4),(0.,0.964458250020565,
1.92950698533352,2.89675569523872,3.86386442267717,4.82732999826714,5.7908281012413,
6.753866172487,7.71725473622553,8.73045394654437,9.74368935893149,10.7574461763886,
11.7708523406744,12.8245096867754,13.8782028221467,14.9315613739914,15.9848526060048,
16.9871588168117,17.9894354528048,18.991393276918,19.9933158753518,20.938877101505,
21.8843961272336,22.8299491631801,23.7755289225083,24.7351424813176,25.6951017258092,
26.6551468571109,27.6152425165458,28.6384069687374,29.6616103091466,30.68508944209,
31.7086868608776,32.761486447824,33.8138309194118,34.8658559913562,35.9177963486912,
36.9054658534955,37.8930948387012,38.8804624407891,39.867805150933,40.7988037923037,
41.7297594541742,42.6607024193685,43.5920093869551,44.5606818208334,45.5297837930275,
46.4990137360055,47.4682816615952,48.5094270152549,49.550214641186,50.5912835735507,
51.6323288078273,52.6732059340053,53.7140920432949,54.7545125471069,55.7948626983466,
56.767289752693,57.7396719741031,58.7119189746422,59.6841623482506,60.6264621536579,
61.5687353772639,62.5109616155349,63.4535532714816,64.4374037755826,65.4216964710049,
66.4061340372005,67.3906017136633,68.4362909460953,69.4816258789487,70.5273965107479,
71.5730217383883,72.5247944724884,73.4764535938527,74.4258307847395,75.3746561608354,
75.7824554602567,76.1902846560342),.UNSPECIFIED.);
#606=CARTESIAN_POINT('',(0.,27.495454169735,12.));
#607=VERTEX_POINT('',#606);
#608=EDGE_CURVE('E71',#607,#607,#605,.T.);
#609=ORIENTED_EDGE('',*,*,#608,.T.);
#610=EDGE_LOOP('',(#609));
#611=FACE_BOUND('',#610,.T.);
#612=ORIENTED_EDGE('',*,*,#439,.T.);
#613=EDGE_LOOP('',(#612));
#614=FACE_BOUND('',#613,.T.);
#615=ADVANCED_FACE('F78',(#611,#614),#213,.F.);
#616=CARTESIAN_POINT('',(17.5,0.,30.));
#617=CARTESIAN_POINT('',(17.4999968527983,-0.449810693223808,29.9999971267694));
#618=CARTESIAN_POINT('',(17.4826284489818,-0.899793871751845,29.9898563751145));
#619=CARTESIAN_POINT('',(17.4133677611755,-1.79639765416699,29.9495342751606));
#620=CARTESIAN_POINT('',(17.361451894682,-2.24301575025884,29.919339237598));
#621=CARTESIAN_POINT('',(17.2236137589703,-3.13036631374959,29.8395660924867));
#622=CARTESIAN_POINT('',(17.1376074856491,-3.57108144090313,29.789940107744));
#623=CARTESIAN_POINT('',(16.9327162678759,-4.44222245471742,29.6725435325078));
#624=CARTESIAN_POINT('',(16.8138366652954,-4.8726500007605,29.6047758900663));
#625=CARTESIAN_POINT('',(16.5452616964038,-5.71841043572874,29.453072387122));
#626=CARTESIAN_POINT('',(16.3957215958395,-6.13380743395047,29.3692181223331));
#627=CARTESIAN_POINT('',(16.0670205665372,-6.94940208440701,29.1869910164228));
#628=CARTESIAN_POINT('',(15.8878585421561,-7.34959917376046,29.0886176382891));
#629=CARTESIAN_POINT('',(15.5016401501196,-8.13262843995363,28.8794824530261));
#630=CARTESIAN_POINT('',(15.2945981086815,-8.5154694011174,28.7687270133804));
#631=CARTESIAN_POINT('',(14.8541334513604,-9.26243782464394,28.5369970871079));
#632=CARTESIAN_POINT('',(14.6207082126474,-9.62656342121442,28.4160215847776));
#633=CARTESIAN_POINT('',(14.1107946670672,-10.3609767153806,28.1569314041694));
#634=CARTESIAN_POINT('',(13.8323977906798,-10.7297256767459,28.0182109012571));
#635=CARTESIAN_POINT('',(13.2486479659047,-11.4427112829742,27.7346638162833));
#636=CARTESIAN_POINT('',(12.9432938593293,-11.7869468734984,27.5898369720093));
#637=CARTESIAN_POINT('',(12.3067916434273,-12.4500740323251,27.2970177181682));
#638=CARTESIAN_POINT('',(11.9756138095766,-12.7689355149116,27.1490218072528));
#639=CARTESIAN_POINT('',(11.2891441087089,-13.3796980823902,26.853283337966));
#640=CARTESIAN_POINT('',(10.9338509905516,-13.6715977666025,26.7055407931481));
#641=CARTESIAN_POINT('',(10.1583817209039,-14.259039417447,26.3970089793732));
#642=CARTESIAN_POINT('',(9.73543487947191,-14.5511698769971,26.2366633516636));
#643=CARTESIAN_POINT('',(8.86283360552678,-15.0985250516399,25.9255412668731));
#644=CARTESIAN_POINT('',(8.41317514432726,-15.3537441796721,25.774766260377));
#645=CARTESIAN_POINT('',(7.48977052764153,-15.8247150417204,25.4883167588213));
#646=CARTESIAN_POINT('',(7.01605587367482,-16.0405167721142,25.3526232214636));
#647=CARTESIAN_POINT('',(6.04663430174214,-16.4304876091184,25.1016518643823));
#648=CARTESIAN_POINT('',(5.55093507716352,-16.6046711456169,24.9863669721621));
#649=CARTESIAN_POINT('',(4.65706076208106,-16.8738511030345,24.8051015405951));
#650=CARTESIAN_POINT('',(4.26263870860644,-16.9778465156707,24.7338784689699));
#651=CARTESIAN_POINT('',(3.46485026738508,-17.1584379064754,24.6089435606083));
#652=CARTESIAN_POINT('',(3.06148523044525,-17.2350379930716,24.5552290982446));
#653=CARTESIAN_POINT('',(2.24867486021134,-17.3597911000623,24.4671923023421));
#654=CARTESIAN_POINT('',(1.8392358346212,-17.4079717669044,24.4328511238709));
#655=CARTESIAN_POINT('',(1.0167506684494,-17.475309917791,24.3847344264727));
#656=CARTESIAN_POINT('',(0.603704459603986,-17.4944668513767,24.3709592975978));
#657=CARTESIAN_POINT('',(-0.223533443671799,-17.5034683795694,24.3644952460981));
#658=CARTESIAN_POINT('',(-0.637725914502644,-17.4932661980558,24.37183997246));
#659=CARTESIAN_POINT('',(-1.46344007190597,-17.4436068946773,24.4074066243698));
#660=CARTESIAN_POINT('',(-1.87496174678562,-17.4041496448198,24.4356286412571));
#661=CARTESIAN_POINT('',(-2.692603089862,-17.2965326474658,24.5119213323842));
#662=CARTESIAN_POINT('',(-3.09871931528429,-17.2283554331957,24.5600040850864));
#663=CARTESIAN_POINT('',(-3.90267086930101,-17.0642171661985,24.674328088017));
#664=CARTESIAN_POINT('',(-4.30050600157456,-16.9682554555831,24.7405697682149));
#665=CARTESIAN_POINT('',(-5.08267223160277,-16.7505223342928,24.8884945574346));
#666=CARTESIAN_POINT('',(-5.46708355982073,-16.6289547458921,24.970055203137));
#667=CARTESIAN_POINT('',(-6.22398496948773,-16.3607241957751,25.1466195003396));
#668=CARTESIAN_POINT('',(-6.59647109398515,-16.2140530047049,25.2416275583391));
#669=CARTESIAN_POINT('',(-7.32806526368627,-15.8968063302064,25.4426176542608));
#670=CARTESIAN_POINT('',(-7.6871723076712,-15.7262290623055,25.5486005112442));
#671=CARTESIAN_POINT('',(-8.39091146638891,-15.3622772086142,25.7690843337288));
#672=CARTESIAN_POINT('',(-8.73554280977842,-15.1689014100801,25.8835857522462));
#673=CARTESIAN_POINT('',(-9.46560202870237,-14.7262927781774,26.1383221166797));
#674=CARTESIAN_POINT('',(-9.84826032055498,-14.4731215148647,26.2796660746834));
#675=CARTESIAN_POINT('',(-10.5913084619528,-13.938566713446,26.5670554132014));
#676=CARTESIAN_POINT('',(-10.9517021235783,-13.6571880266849,26.7130999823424));
#677=CARTESIAN_POINT('',(-11.6494208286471,-13.0671312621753,27.0066427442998));
#678=CARTESIAN_POINT('',(-11.9867237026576,-12.7584275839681,27.1541421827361));
#679=CARTESIAN_POINT('',(-12.6365789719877,-12.1151118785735,27.4472042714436));
#680=CARTESIAN_POINT('',(-12.9491301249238,-11.7804985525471,27.5927668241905));
#681=CARTESIAN_POINT('',(-13.5852520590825,-11.0433879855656,27.8966228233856));
#682=CARTESIAN_POINT('',(-13.905367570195,-10.6376217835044,28.0542511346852));
#683=CARTESIAN_POINT('',(-14.5101413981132,-9.79663499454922,28.358878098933));
#684=CARTESIAN_POINT('',(-14.7947962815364,-9.36141156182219,28.5058757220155));
#685=CARTESIAN_POINT('',(-15.3258939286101,-8.46396420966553,28.7851006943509));
#686=CARTESIAN_POINT('',(-15.5723530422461,-8.00175196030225,28.9173343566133));
#687=CARTESIAN_POINT('',(-16.024383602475,-7.0530224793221,29.1632455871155));
#688=CARTESIAN_POINT('',(-16.2299601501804,-6.56650828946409,29.2769254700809));
#689=CARTESIAN_POINT('',(-16.585129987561,-5.60604764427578,29.4753513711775));
#690=CARTESIAN_POINT('',(-16.7375511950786,-5.13344287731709,29.5615255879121));
#691=CARTESIAN_POINT('',(-17.0022860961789,-4.17372530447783,29.7122175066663));
#692=CARTESIAN_POINT('',(-17.114601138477,-3.68661298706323,29.776735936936));
#693=CARTESIAN_POINT('',(-17.2973035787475,-2.70250384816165,29.8821207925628));
#694=CARTESIAN_POINT('',(-17.3677283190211,-2.20551623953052,29.9230082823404));
#695=CARTESIAN_POINT('',(-17.4656178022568,-1.2059347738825,29.9799298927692));
#696=CARTESIAN_POINT('',(-17.4930878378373,-0.703341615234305,29.9959670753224));
#697=CARTESIAN_POINT('',(-17.5038812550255,0.238332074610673,30.0022648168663));
#698=CARTESIAN_POINT('',(-17.4923847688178,0.677343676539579,29.9955500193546));
#699=CARTESIAN_POINT('',(-17.4365101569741,1.55252162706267,29.962999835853));
#700=CARTESIAN_POINT('',(-17.39213540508,1.98868826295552,29.9371664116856));
#701=CARTESIAN_POINT('',(-17.2710852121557,2.85498146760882,29.8670045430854));
#702=CARTESIAN_POINT('',(-17.1944102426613,3.28510812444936,29.8226763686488));
#703=CARTESIAN_POINT('',(-17.009706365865,4.13637468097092,29.7165677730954));
#704=CARTESIAN_POINT('',(-16.9016765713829,4.55751432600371,29.654786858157));
#705=CARTESIAN_POINT('',(-16.6574538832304,5.38154043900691,29.5162806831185));
#706=CARTESIAN_POINT('',(-16.5217352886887,5.78461054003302,29.439808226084));
#707=CARTESIAN_POINT('',(-16.2224830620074,6.57727299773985,29.2729147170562));
#708=CARTESIAN_POINT('',(-16.058950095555,6.96686567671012,29.1824939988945));
#709=CARTESIAN_POINT('',(-15.7054857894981,7.73077402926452,28.989487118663));
#710=CARTESIAN_POINT('',(-15.5155522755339,8.10508844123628,28.8868999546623));
#711=CARTESIAN_POINT('',(-15.1107192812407,8.83691529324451,28.6714922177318));
#712=CARTESIAN_POINT('',(-14.8958168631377,9.19442574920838,28.5586704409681));
#713=CARTESIAN_POINT('',(-14.4187917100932,9.9276976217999,28.3126392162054));
#714=CARTESIAN_POINT('',(-14.1540817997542,10.3014755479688,28.178530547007));
#715=CARTESIAN_POINT('',(-13.5976432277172,11.0255438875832,27.9031798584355));
#716=CARTESIAN_POINT('',(-13.3059129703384,11.3758329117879,27.7619374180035));
#717=CARTESIAN_POINT('',(-12.6966614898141,12.0520590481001,27.4751323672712));
#718=CARTESIAN_POINT('',(-12.3791126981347,12.3779693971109,27.3295652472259));
#719=CARTESIAN_POINT('',(-11.719891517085,13.0038744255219,27.0373548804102));
#720=CARTESIAN_POINT('',(-11.3782184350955,13.3038683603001,26.8907116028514));
#721=CARTESIAN_POINT('',(-10.629716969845,13.9110859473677,26.5821575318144));
#722=CARTESIAN_POINT('',(-10.219984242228,14.2148796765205,26.4205194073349));
#723=CARTESIAN_POINT('',(-9.37347588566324,14.7867809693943,26.1047476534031));
#724=CARTESIAN_POINT('',(-8.93669617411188,15.0548831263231,25.9506151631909));
#725=CARTESIAN_POINT('',(-8.03840403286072,15.5530565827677,25.6551405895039));
#726=CARTESIAN_POINT('',(-7.57691649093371,15.7831652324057,25.5137860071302));
#727=CARTESIAN_POINT('',(-6.63112032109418,16.2032645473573,25.2490774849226));
#728=CARTESIAN_POINT('',(-6.14681879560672,16.3932675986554,25.1257179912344));
#729=CARTESIAN_POINT('',(-5.26494928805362,16.6942555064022,24.9264319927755));
#730=CARTESIAN_POINT('',(-4.87118142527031,16.8134449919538,24.8460125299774));
#731=CARTESIAN_POINT('',(-4.07333959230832,17.0243377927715,24.7019890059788));
#732=CARTESIAN_POINT('',(-3.66926705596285,17.1160449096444,24.6383826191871));
#733=CARTESIAN_POINT('',(-2.85358320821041,17.270761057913,24.5301802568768));
#734=CARTESIAN_POINT('',(-2.44198036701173,17.3338004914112,24.4855641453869));
#735=CARTESIAN_POINT('',(-1.61360456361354,17.430437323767,24.4168669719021));
#736=CARTESIAN_POINT('',(-1.19683154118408,17.4640343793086,24.3927861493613));
#737=CARTESIAN_POINT('',(-0.360120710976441,17.5013184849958,24.3660499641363));
#738=CARTESIAN_POINT('',(0.0598226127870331,17.5049242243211,24.3634528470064));
#739=CARTESIAN_POINT('',(0.898450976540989,17.4819549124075,24.3799394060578));
#740=CARTESIAN_POINT('',(1.3171360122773,17.4553797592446,24.3990231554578));
#741=CARTESIAN_POINT('',(2.15025222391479,17.3724427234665,24.4581439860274));
#742=CARTESIAN_POINT('',(2.5646810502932,17.3160652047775,24.4981920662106));
#743=CARTESIAN_POINT('',(3.38615200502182,17.1743332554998,24.5977590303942));
#744=CARTESIAN_POINT('',(3.79319403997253,17.0889784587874,24.657278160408));
#745=CARTESIAN_POINT('',(4.58544224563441,16.8933493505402,24.7916997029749));
#746=CARTESIAN_POINT('',(4.97093786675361,16.7838907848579,24.8660925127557));
#747=CARTESIAN_POINT('',(5.73091273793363,16.5398304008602,25.0290936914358));
#748=CARTESIAN_POINT('',(6.10538834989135,16.4052203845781,25.11770669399));
#749=CARTESIAN_POINT('',(6.84175460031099,16.1120287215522,25.3067765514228));
#750=CARTESIAN_POINT('',(7.20364427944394,15.9534452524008,25.407234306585));
#751=CARTESIAN_POINT('',(7.91366058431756,15.6134217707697,25.6175920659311));
#752=CARTESIAN_POINT('',(8.26178655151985,15.4319806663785,25.7274925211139));
#753=CARTESIAN_POINT('',(8.99622181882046,15.0174007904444,25.9719887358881));
#754=CARTESIAN_POINT('',(9.38007737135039,14.780608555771,26.1077707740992));
#755=CARTESIAN_POINT('',(10.1268432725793,14.2793303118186,26.3852759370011));
#756=CARTESIAN_POINT('',(10.4897570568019,14.01484886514,26.5269980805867));
#757=CARTESIAN_POINT('',(11.1938616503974,13.4591512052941,26.8132242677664));
#758=CARTESIAN_POINT('',(11.5350346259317,13.1679135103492,26.9577304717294));
#759=CARTESIAN_POINT('',(12.1941478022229,12.5600071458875,27.2462739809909));
#760=CARTESIAN_POINT('',(12.5120867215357,12.2433370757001,27.3903112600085));
#761=CARTESIAN_POINT('',(13.1663568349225,11.5394613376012,27.6949046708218));
#762=CARTESIAN_POINT('',(13.4990058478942,11.1485939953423,27.8549417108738));
#763=CARTESIAN_POINT('',(14.1302209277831,10.3368854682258,28.1662522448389));
#764=CARTESIAN_POINT('',(14.4287831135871,9.91604087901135,28.3175247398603));
#765=CARTESIAN_POINT('',(14.9894358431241,9.046247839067,28.6072642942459));
#766=CARTESIAN_POINT('',(15.2515119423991,8.59728835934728,28.7457262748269));
#767=CARTESIAN_POINT('',(15.7363172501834,7.67398823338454,29.0058586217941));
#768=CARTESIAN_POINT('',(15.9590523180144,7.19965138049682,29.1275314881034));
#769=CARTESIAN_POINT('',(16.3528613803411,6.25177433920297,29.3451946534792));
#770=CARTESIAN_POINT('',(16.5258832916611,5.77926155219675,29.4421287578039));
#771=CARTESIAN_POINT('',(16.8314407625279,4.81738564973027,29.6147173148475));
#772=CARTESIAN_POINT('',(16.9639692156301,4.32801959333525,29.6903680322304));
#773=CARTESIAN_POINT('',(17.1860844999,3.33838985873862,29.8178345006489));
#774=CARTESIAN_POINT('',(17.2758169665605,2.83816928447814,29.8697310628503));
#775=CARTESIAN_POINT('',(17.4114535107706,1.83015669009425,29.948382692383));
#776=CARTESIAN_POINT('',(17.4573967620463,1.32237185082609,29.975160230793));
#777=CARTESIAN_POINT('',(17.4873882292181,0.678004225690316,29.9926448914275));
#778=CARTESIAN_POINT('',(17.4921161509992,0.542466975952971,29.9954016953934));
#779=CARTESIAN_POINT('',(17.4984225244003,0.271291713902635,29.9990796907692));
#780=CARTESIAN_POINT('',(17.5000009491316,0.13565370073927,30.0000008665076));
#781=CARTESIAN_POINT('',(17.5,0.,30.));
#782=B_SPLINE_CURVE_WITH_KNOTS('',3,(#616,#617,#618,#619,#620,#621,#622,#623,#624,#625,#626,
#627,#628,#629,#630,#631,#632,#633,#634,#635,#636,#637,#638,#639,#640,#641,#642,#643,#644,#645,
#646,#647,#648,#649,#650,#651,#652,#653,#654,#655,#656,#657,#658,#659,#660,#661,#662,#663,#664,
#665,#666,#667,#668,#669,#670,#671,#672,#673,#674,#675,#676,#677,#678,#679,#680,#681,#682,#683,
#684,#685,#686,#687,#688,#689,#690,#691,#692,#693,#694,#695,#696,#697,#698,#699,#700,#701,#702,
#703,#704,#705,#706,#707,#708,#709,#710,#711,#712,#713,#714,#715,#716,#717,#718,#719,#720,#721,
#722,#723,#724,#725,#726,#727,#728,#729,#730,#731,#732,#733,#734,#735,#736,#737,#738,#739,#740,
#741,#742,#743,#744,#745,#746,#747,#748,#749,#750,#751,#752,#753,#754,#755,#756,#757,#758,#759,
#760,#761,#762,#763,#764,#765,#766,#767,#768,#769,#770,#771,#772,#773,#774,#775,#776,#777,#778,
#779,#780,#781),.UNSPECIFIED.,.T.,.F.,(4,2,2,2,2,2,2,2,2,2,2,2,2,2,2,2,2,2,2,2,2,2,2,2,2,2,2,2,
2,2,2,2,2,2,2,2,2,2,2,2,2,2,2,2,2,2,2,2,2,2,2,2,2,2,2,2,2,2,2,2,2,2,2,2,2,2,2,2,2,2,2,2,2,2,2,2,
2,2,2,2,2,2,4),(0.,1.3492851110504,2.69949220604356,4.05304731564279,5.4063826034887,
6.75302671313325,8.09972064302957,9.44572519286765,10.7918636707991,12.2376383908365,
13.6834752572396,15.1310016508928,16.5786032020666,18.1919933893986,19.8056275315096,
21.4172005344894,23.0282139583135,24.2691750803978,25.509950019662,26.7495159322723,
27.9891053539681,29.2306708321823,30.4722417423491,31.7145688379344,32.9569253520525,
34.1897431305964,35.4229658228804,36.6562806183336,37.8896610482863,39.3285368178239,
40.7671655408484,42.2071566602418,43.6472200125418,45.2661955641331,46.8853277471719,
48.503764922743,50.1220000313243,51.6318206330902,53.1415904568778,54.6500124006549,
56.1582484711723,57.474265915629,58.7901483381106,60.106011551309,61.4219120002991,
62.7169231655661,64.0119033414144,65.306990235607,66.6022296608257,68.0325140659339,
69.462882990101,70.8947998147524,72.3267577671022,73.9300541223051,75.5335930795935,
77.1355461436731,78.7370037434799,79.9933457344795,81.249513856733,82.5043466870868,
83.7591941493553,85.0174425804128,86.2756952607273,87.5346087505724,88.7935381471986,
90.015062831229,91.2369863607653,92.4590028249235,93.6810776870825,95.0927219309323,
96.5041339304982,97.9166891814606,99.3293222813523,100.940233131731,102.551327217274,
104.163057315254,105.774547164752,107.309672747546,108.845067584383,110.375199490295,
111.903961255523,112.310874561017,112.717791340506),.UNSPECIFIED.);
#783=CARTESIAN_POINT('',(17.5,0.,30.));
#784=VERTEX_POINT('',#783);
#785=EDGE_CURVE('E56',#784,#784,#782,.T.);
#786=ORIENTED_EDGE('',*,*,#785,.T.);
#787=EDGE_LOOP('',(#786));
#788=FACE_BOUND('',#787,.T.);
#789=ORIENTED_EDGE('',*,*,#425,.T.);
#790=EDGE_LOOP('',(#789));
#791=FACE_BOUND('',#790,.T.);
#792=ADVANCED_FACE('F60',(#788,#791),#23,.F.);
#793=CARTESIAN_POINT('',(-75.,0.,0.));
#794=DIRECTION('',(1.,0.,0.));
#795=DIRECTION('',(0.,0.,-1.));
#796=AXIS2_PLACEMENT_3D('',#793,#794,#795);
#797=CYLINDRICAL_SURFACE('',#796,30.);
#798=ORIENTED_EDGE('',*,*,#608,.F.);
#799=EDGE_LOOP('',(#798));
#800=FACE_BOUND('',#799,.T.);
#801=ORIENTED_EDGE('',*,*,#785,.F.);
#802=EDGE_LOOP('',(#801));
#803=FACE_BOUND('',#802,.T.);
#804=ORIENTED_EDGE('',*,*,#193,.F.);
#805=EDGE_LOOP('',(#804));
#806=FACE_BOUND('',#805,.T.);
#807=ORIENTED_EDGE('',*,*,#414,.T.);
#808=EDGE_LOOP('',(#807));
#809=FACE_BOUND('',#808,.T.);
#810=ORIENTED_EDGE('',*,*,#403,.T.);
#811=EDGE_LOOP('',(#810));
#812=FACE_BOUND('',#811,.T.);
#813=ORIENTED_EDGE('',*,*,#375,.F.);
#814=EDGE_LOOP('',(#813));
#815=FACE_BOUND('',#814,.T.);
#816=ADVANCED_FACE('F62',(#800,#803,#806,#809,#812,#815),#797,.F.);
#817=CLOSED_SHELL('',(#208,#390,#446,#615,#792,#816));
#818=MANIFOLD_SOLID_BREP('B2',#817);
#819=ADVANCED_BREP_SHAPE_REPRESENTATION('',(#18,#818),#14);
#820=SHAPE_DEFINITION_REPRESENTATION(#9,#819);
ENDSEC;
END-ISO-10303-21;
